# LEF abstracts for the cells placed in sample.gds
# fetched from google/skywater-pdk-libs-sky130_fd_sc_hd

VERSION 5.5 ;
BUSBITCHARS "[]" ;
DIVIDERCHAR "/" ;

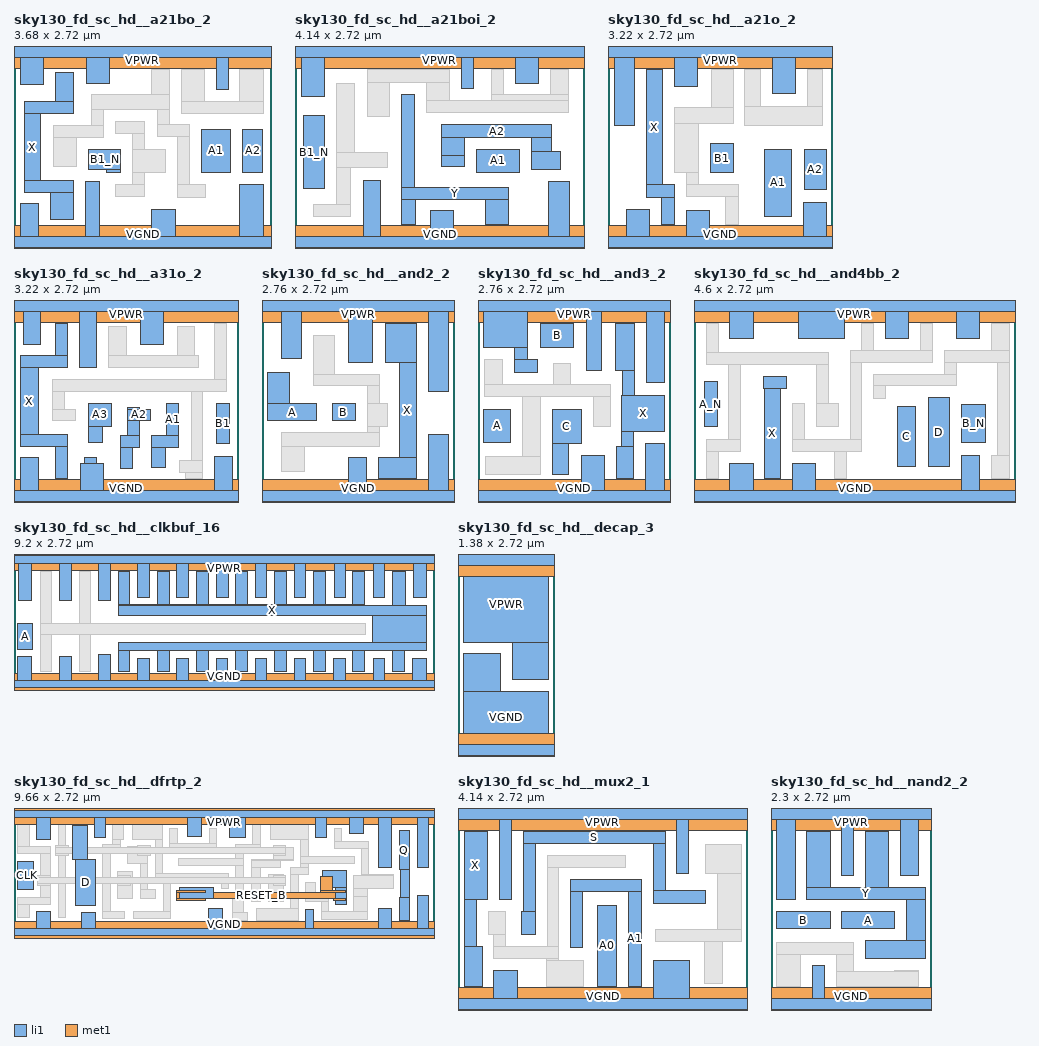
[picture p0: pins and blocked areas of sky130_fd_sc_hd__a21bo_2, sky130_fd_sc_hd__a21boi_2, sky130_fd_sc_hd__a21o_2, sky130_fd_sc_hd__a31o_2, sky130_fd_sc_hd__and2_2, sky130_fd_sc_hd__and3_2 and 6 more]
MACRO sky130_fd_sc_hd__a21bo_2
  CLASS CORE ;
  SOURCE USER ;
  ORIGIN  0.000000  0.000000 ;
  SIZE  3.680000 BY  2.720000 ;
  SYMMETRY X Y R90 ;
  SITE unithd ;
  PIN A1
    ANTENNAGATEAREA  0.247500 ;
    DIRECTION INPUT ;
    USE SIGNAL ;
    PORT
      LAYER li1 ;
        RECT 2.685000 0.995000 3.100000 1.615000 ;
    END
  END A1
  PIN A2
    ANTENNAGATEAREA  0.247500 ;
    DIRECTION INPUT ;
    USE SIGNAL ;
    PORT
      LAYER li1 ;
        RECT 3.270000 0.995000 3.560000 1.615000 ;
    END
  END A2
  PIN B1_N
    ANTENNAGATEAREA  0.126000 ;
    DIRECTION INPUT ;
    USE SIGNAL ;
    PORT
      LAYER li1 ;
        RECT 1.070000 1.035000 1.525000 1.325000 ;
        RECT 1.330000 0.995000 1.525000 1.035000 ;
    END
  END B1_N
  PIN X
    ANTENNADIFFAREA  0.462000 ;
    DIRECTION OUTPUT ;
    USE SIGNAL ;
    PORT
      LAYER li1 ;
        RECT 0.150000 0.715000 0.850000 0.885000 ;
        RECT 0.150000 0.885000 0.380000 1.835000 ;
        RECT 0.150000 1.835000 0.850000 2.005000 ;
        RECT 0.520000 0.315000 0.850000 0.715000 ;
        RECT 0.595000 2.005000 0.850000 2.425000 ;
    END
  END X
  PIN VGND
    DIRECTION INOUT ;
    SHAPE ABUTMENT ;
    USE GROUND ;
    PORT
      LAYER li1 ;
        RECT 0.000000 -0.085000 3.680000 0.085000 ;
        RECT 0.090000  0.085000 0.345000 0.545000 ;
        RECT 1.020000  0.085000 1.220000 0.865000 ;
        RECT 1.975000  0.085000 2.305000 0.465000 ;
        RECT 3.235000  0.085000 3.565000 0.825000 ;
    END
    PORT
      LAYER met1 ;
        RECT 0.000000 -0.240000 3.680000 0.240000 ;
    END
  END VGND
  PIN VPWR
    DIRECTION INOUT ;
    SHAPE ABUTMENT ;
    USE POWER ;
    PORT
      LAYER li1 ;
        RECT 0.000000 2.635000 3.680000 2.805000 ;
        RECT 0.090000 2.255000 0.425000 2.635000 ;
        RECT 1.040000 2.275000 1.370000 2.635000 ;
        RECT 2.895000 2.185000 3.065000 2.635000 ;
    END
    PORT
      LAYER met1 ;
        RECT 0.000000 2.480000 3.680000 2.960000 ;
    END
  END VPWR
  OBS
    LAYER li1 ;
      RECT 0.570000 1.075000 0.900000 1.495000 ;
      RECT 0.570000 1.495000 1.285000 1.665000 ;
      RECT 1.115000 1.665000 1.285000 1.895000 ;
      RECT 1.115000 1.895000 2.225000 2.105000 ;
      RECT 1.455000 0.655000 1.865000 0.825000 ;
      RECT 1.455000 1.555000 1.865000 1.725000 ;
      RECT 1.695000 0.825000 1.865000 0.995000 ;
      RECT 1.695000 0.995000 2.175000 1.325000 ;
      RECT 1.695000 1.325000 1.865000 1.555000 ;
      RECT 1.975000 2.105000 2.225000 2.465000 ;
      RECT 2.055000 1.505000 2.515000 1.675000 ;
      RECT 2.055000 1.675000 2.225000 1.895000 ;
      RECT 2.345000 0.635000 2.740000 0.825000 ;
      RECT 2.345000 0.825000 2.515000 1.505000 ;
      RECT 2.395000 1.845000 3.565000 2.015000 ;
      RECT 2.395000 2.015000 2.725000 2.465000 ;
      RECT 3.235000 2.015000 3.565000 2.465000 ;
  END
END sky130_fd_sc_hd__a21bo_2
MACRO sky130_fd_sc_hd__a21boi_2
  CLASS CORE ;
  SOURCE USER ;
  ORIGIN  0.000000  0.000000 ;
  SIZE  4.140000 BY  2.720000 ;
  SYMMETRY X Y R90 ;
  SITE unithd ;
  PIN A1
    ANTENNAGATEAREA  0.495000 ;
    DIRECTION INPUT ;
    USE SIGNAL ;
    PORT
      LAYER li1 ;
        RECT 2.605000 0.995000 3.215000 1.325000 ;
    END
  END A1
  PIN A2
    ANTENNAGATEAREA  0.495000 ;
    DIRECTION INPUT ;
    USE SIGNAL ;
    PORT
      LAYER li1 ;
        RECT 2.095000 1.075000 2.425000 1.245000 ;
        RECT 2.100000 1.245000 2.425000 1.495000 ;
        RECT 2.100000 1.495000 3.675000 1.675000 ;
        RECT 3.385000 1.035000 3.795000 1.295000 ;
        RECT 3.385000 1.295000 3.675000 1.495000 ;
    END
  END A2
  PIN B1_N
    ANTENNAGATEAREA  0.126000 ;
    DIRECTION INPUT ;
    USE SIGNAL ;
    PORT
      LAYER li1 ;
        RECT 0.120000 0.765000 0.425000 1.805000 ;
    END
  END B1_N
  PIN Y
    ANTENNADIFFAREA  0.627500 ;
    DIRECTION OUTPUT ;
    USE SIGNAL ;
    PORT
      LAYER li1 ;
        RECT 1.520000 0.255000 1.720000 0.615000 ;
        RECT 1.520000 0.615000 3.060000 0.785000 ;
        RECT 1.520000 0.785000 1.715000 2.115000 ;
        RECT 2.730000 0.255000 3.060000 0.615000 ;
    END
  END Y
  PIN VGND
    DIRECTION INOUT ;
    SHAPE ABUTMENT ;
    USE GROUND ;
    PORT
      LAYER li1 ;
        RECT 0.000000 -0.085000 4.140000 0.085000 ;
        RECT 0.985000  0.085000 1.225000 0.885000 ;
        RECT 1.940000  0.085000 2.270000 0.445000 ;
        RECT 3.635000  0.085000 3.930000 0.865000 ;
    END
    PORT
      LAYER met1 ;
        RECT 0.000000 -0.240000 4.140000 0.240000 ;
    END
  END VGND
  PIN VPWR
    DIRECTION INOUT ;
    SHAPE ABUTMENT ;
    USE POWER ;
    PORT
      LAYER li1 ;
        RECT 0.000000 2.635000 4.140000 2.805000 ;
        RECT 0.095000 2.080000 0.425000 2.635000 ;
        RECT 2.385000 2.195000 2.555000 2.635000 ;
        RECT 3.160000 2.275000 3.490000 2.635000 ;
    END
    PORT
      LAYER met1 ;
        RECT 0.000000 2.480000 4.140000 2.960000 ;
    END
  END VPWR
  OBS
    LAYER li1 ;
      RECT 0.265000 0.360000 0.795000 0.530000 ;
      RECT 0.595000 0.530000 0.795000 1.070000 ;
      RECT 0.595000 1.070000 1.325000 1.285000 ;
      RECT 0.595000 1.285000 0.855000 2.265000 ;
      RECT 1.045000 1.795000 1.350000 2.285000 ;
      RECT 1.045000 2.285000 2.215000 2.465000 ;
      RECT 1.885000 1.855000 3.920000 2.025000 ;
      RECT 1.885000 2.025000 2.215000 2.285000 ;
      RECT 2.810000 2.025000 3.920000 2.105000 ;
      RECT 2.810000 2.105000 2.980000 2.465000 ;
      RECT 3.660000 2.105000 3.920000 2.465000 ;
  END
END sky130_fd_sc_hd__a21boi_2
MACRO sky130_fd_sc_hd__a21o_2
  CLASS CORE ;
  SOURCE USER ;
  ORIGIN  0.000000  0.000000 ;
  SIZE  3.220000 BY  2.720000 ;
  SYMMETRY X Y R90 ;
  SITE unithd ;
  PIN A1
    ANTENNAGATEAREA  0.247500 ;
    DIRECTION INPUT ;
    USE SIGNAL ;
    PORT
      LAYER li1 ;
        RECT 2.240000 0.365000 2.620000 1.325000 ;
    END
  END A1
  PIN A2
    ANTENNAGATEAREA  0.247500 ;
    DIRECTION INPUT ;
    USE SIGNAL ;
    PORT
      LAYER li1 ;
        RECT 2.810000 0.750000 3.125000 1.325000 ;
    END
  END A2
  PIN B1
    ANTENNAGATEAREA  0.247500 ;
    DIRECTION INPUT ;
    USE SIGNAL ;
    PORT
      LAYER li1 ;
        RECT 1.465000 0.995000 1.790000 1.410000 ;
    END
  END B1
  PIN X
    ANTENNADIFFAREA  0.462000 ;
    DIRECTION OUTPUT ;
    USE SIGNAL ;
    PORT
      LAYER li1 ;
        RECT 0.555000 0.635000 0.955000 0.825000 ;
        RECT 0.555000 0.825000 0.785000 2.465000 ;
        RECT 0.765000 0.255000 0.955000 0.635000 ;
    END
  END X
  PIN VGND
    DIRECTION INOUT ;
    SHAPE ABUTMENT ;
    USE GROUND ;
    PORT
      LAYER li1 ;
        RECT 0.000000 -0.085000 3.220000 0.085000 ;
        RECT 0.265000  0.085000 0.595000 0.465000 ;
        RECT 1.125000  0.085000 1.455000 0.445000 ;
        RECT 2.805000  0.085000 3.135000 0.565000 ;
    END
    PORT
      LAYER met1 ;
        RECT 0.000000 -0.240000 3.220000 0.240000 ;
    END
  END VGND
  PIN VPWR
    DIRECTION INOUT ;
    SHAPE ABUTMENT ;
    USE POWER ;
    PORT
      LAYER li1 ;
        RECT 0.000000 2.635000 3.220000 2.805000 ;
        RECT 0.095000 1.665000 0.385000 2.635000 ;
        RECT 0.955000 2.220000 1.285000 2.635000 ;
        RECT 2.355000 2.125000 2.685000 2.635000 ;
    END
    PORT
      LAYER met1 ;
        RECT 0.000000 2.480000 3.220000 2.960000 ;
    END
  END VPWR
  OBS
    LAYER li1 ;
      RECT 0.955000 0.995000 1.295000 1.690000 ;
      RECT 0.955000 1.690000 1.790000 1.920000 ;
      RECT 1.125000 0.655000 1.865000 0.825000 ;
      RECT 1.125000 0.825000 1.295000 0.995000 ;
      RECT 1.475000 1.920000 1.790000 2.465000 ;
      RECT 1.675000 0.255000 1.865000 0.655000 ;
      RECT 1.960000 1.670000 3.075000 1.935000 ;
      RECT 1.960000 1.935000 2.185000 2.465000 ;
      RECT 2.855000 1.935000 3.075000 2.465000 ;
  END
END sky130_fd_sc_hd__a21o_2
MACRO sky130_fd_sc_hd__a31o_2
  CLASS CORE ;
  SOURCE USER ;
  ORIGIN  0.000000  0.000000 ;
  SIZE  3.220000 BY  2.720000 ;
  SYMMETRY X Y R90 ;
  SITE unithd ;
  PIN A1
    ANTENNAGATEAREA  0.247500 ;
    DIRECTION INPUT ;
    USE SIGNAL ;
    PORT
      LAYER li1 ;
        RECT 1.965000 0.415000 2.175000 0.700000 ;
        RECT 1.965000 0.700000 2.355000 0.870000 ;
        RECT 2.185000 0.870000 2.355000 1.325000 ;
    END
  END A1
  PIN A2
    ANTENNAGATEAREA  0.247500 ;
    DIRECTION INPUT ;
    USE SIGNAL ;
    PORT
      LAYER li1 ;
        RECT 1.530000 0.400000 1.700000 0.695000 ;
        RECT 1.530000 0.695000 1.795000 0.865000 ;
        RECT 1.625000 0.865000 1.795000 1.075000 ;
        RECT 1.625000 1.075000 1.955000 1.245000 ;
        RECT 1.625000 1.245000 1.795000 1.260000 ;
    END
  END A2
  PIN A3
    ANTENNAGATEAREA  0.247500 ;
    DIRECTION INPUT ;
    USE SIGNAL ;
    PORT
      LAYER li1 ;
        RECT 1.065000 0.760000 1.270000 0.995000 ;
        RECT 1.065000 0.995000 1.395000 1.325000 ;
    END
  END A3
  PIN B1
    ANTENNAGATEAREA  0.247500 ;
    DIRECTION INPUT ;
    USE SIGNAL ;
    PORT
      LAYER li1 ;
        RECT 2.895000 0.755000 3.090000 1.325000 ;
    END
  END B1
  PIN X
    ANTENNADIFFAREA  0.445500 ;
    DIRECTION OUTPUT ;
    USE SIGNAL ;
    PORT
      LAYER li1 ;
        RECT 0.090000 0.715000 0.765000 0.885000 ;
        RECT 0.090000 0.885000 0.345000 1.835000 ;
        RECT 0.090000 1.835000 0.765000 2.005000 ;
        RECT 0.595000 0.255000 0.765000 0.715000 ;
        RECT 0.595000 2.005000 0.765000 2.465000 ;
    END
  END X
  PIN VGND
    DIRECTION INOUT ;
    SHAPE ABUTMENT ;
    USE GROUND ;
    PORT
      LAYER li1 ;
        RECT 0.000000 -0.085000 3.220000 0.085000 ;
        RECT 0.090000  0.085000 0.345000 0.545000 ;
        RECT 0.955000  0.085000 1.285000 0.465000 ;
        RECT 1.015000  0.465000 1.185000 0.545000 ;
        RECT 2.875000  0.085000 3.135000 0.565000 ;
    END
    PORT
      LAYER met1 ;
        RECT 0.000000 -0.240000 3.220000 0.240000 ;
    END
  END VGND
  PIN VPWR
    DIRECTION INOUT ;
    SHAPE ABUTMENT ;
    USE POWER ;
    PORT
      LAYER li1 ;
        RECT 0.000000 2.635000 3.220000 2.805000 ;
        RECT 0.135000 2.175000 0.385000 2.635000 ;
        RECT 0.935000 1.835000 1.185000 2.635000 ;
        RECT 1.815000 2.175000 2.145000 2.635000 ;
    END
    PORT
      LAYER met1 ;
        RECT 0.000000 2.480000 3.220000 2.960000 ;
    END
  END VPWR
  OBS
    LAYER li1 ;
      RECT 0.555000 1.075000 0.885000 1.245000 ;
      RECT 0.555000 1.245000 0.725000 1.495000 ;
      RECT 0.555000 1.495000 3.045000 1.665000 ;
      RECT 1.355000 1.835000 2.645000 2.005000 ;
      RECT 1.355000 2.005000 1.605000 2.425000 ;
      RECT 2.335000 2.005000 2.585000 2.425000 ;
      RECT 2.375000 0.335000 2.705000 0.505000 ;
      RECT 2.460000 0.255000 2.705000 0.335000 ;
      RECT 2.535000 0.505000 2.705000 1.495000 ;
      RECT 2.875000 1.665000 3.045000 2.465000 ;
  END
END sky130_fd_sc_hd__a31o_2
MACRO sky130_fd_sc_hd__and2_2
  CLASS CORE ;
  SOURCE USER ;
  ORIGIN  0.000000  0.000000 ;
  SIZE  2.760000 BY  2.720000 ;
  SYMMETRY X Y R90 ;
  SITE unithd ;
  PIN A
    ANTENNAGATEAREA  0.126000 ;
    DIRECTION INPUT ;
    USE SIGNAL ;
    PORT
      LAYER li1 ;
        RECT 0.085000 1.075000 0.775000 1.325000 ;
        RECT 0.085000 1.325000 0.400000 1.765000 ;
    END
  END A
  PIN B
    ANTENNAGATEAREA  0.126000 ;
    DIRECTION INPUT ;
    USE SIGNAL ;
    PORT
      LAYER li1 ;
        RECT 1.005000 1.075000 1.335000 1.325000 ;
    END
  END B
  PIN X
    ANTENNADIFFAREA  0.643500 ;
    DIRECTION OUTPUT ;
    USE SIGNAL ;
    PORT
      LAYER li1 ;
        RECT 1.665000 0.255000 2.215000 0.545000 ;
        RECT 1.765000 1.915000 2.215000 2.465000 ;
        RECT 1.965000 0.545000 2.215000 1.915000 ;
    END
  END X
  PIN VGND
    DIRECTION INOUT ;
    SHAPE ABUTMENT ;
    USE GROUND ;
    PORT
      LAYER li1 ;
        RECT 0.000000 -0.085000 2.760000 0.085000 ;
        RECT 1.245000  0.085000 1.495000 0.545000 ;
        RECT 2.385000  0.085000 2.675000 0.885000 ;
    END
    PORT
      LAYER met1 ;
        RECT 0.000000 -0.240000 2.760000 0.240000 ;
    END
  END VGND
  PIN VPWR
    DIRECTION INOUT ;
    SHAPE ABUTMENT ;
    USE POWER ;
    PORT
      LAYER li1 ;
        RECT 0.000000 2.635000 2.760000 2.805000 ;
        RECT 0.285000 1.965000 0.565000 2.635000 ;
        RECT 1.245000 1.915000 1.575000 2.635000 ;
        RECT 2.385000 1.495000 2.675000 2.635000 ;
    END
    PORT
      LAYER met1 ;
        RECT 0.000000 2.480000 2.760000 2.960000 ;
    END
  END VPWR
  OBS
    LAYER li1 ;
      RECT 0.285000 0.355000 0.615000 0.715000 ;
      RECT 0.285000 0.715000 1.675000 0.905000 ;
      RECT 0.735000 1.575000 1.675000 1.745000 ;
      RECT 0.735000 1.745000 1.035000 2.295000 ;
      RECT 1.505000 0.905000 1.675000 0.995000 ;
      RECT 1.505000 0.995000 1.795000 1.325000 ;
      RECT 1.505000 1.325000 1.675000 1.575000 ;
  END
END sky130_fd_sc_hd__and2_2
MACRO sky130_fd_sc_hd__and3_2
  CLASS CORE ;
  SOURCE USER ;
  ORIGIN  0.000000  0.000000 ;
  SIZE  2.760000 BY  2.720000 ;
  SYMMETRY X Y R90 ;
  SITE unithd ;
  PIN A
    ANTENNAGATEAREA  0.126000 ;
    DIRECTION INPUT ;
    USE SIGNAL ;
    PORT
      LAYER li1 ;
        RECT 0.085000 0.765000 0.470000 1.245000 ;
    END
  END A
  PIN B
    ANTENNAGATEAREA  0.126000 ;
    DIRECTION INPUT ;
    USE SIGNAL ;
    PORT
      LAYER li1 ;
        RECT 0.895000 2.125000 1.370000 2.465000 ;
    END
  END B
  PIN C
    ANTENNAGATEAREA  0.126000 ;
    DIRECTION INPUT ;
    USE SIGNAL ;
    PORT
      LAYER li1 ;
        RECT 1.065000 0.305000 1.295000 0.750000 ;
        RECT 1.065000 0.750000 1.475000 1.245000 ;
    END
  END C
  PIN X
    ANTENNADIFFAREA  0.445500 ;
    DIRECTION OUTPUT ;
    USE SIGNAL ;
    PORT
      LAYER li1 ;
        RECT 1.970000 1.795000 2.245000 2.465000 ;
        RECT 1.980000 0.255000 2.230000 0.715000 ;
        RECT 2.060000 0.715000 2.230000 0.925000 ;
        RECT 2.060000 0.925000 2.675000 1.445000 ;
        RECT 2.075000 1.445000 2.245000 1.795000 ;
    END
  END X
  PIN VGND
    DIRECTION INOUT ;
    SHAPE ABUTMENT ;
    USE GROUND ;
    PORT
      LAYER li1 ;
        RECT 0.000000 -0.085000 2.760000 0.085000 ;
        RECT 1.475000  0.085000 1.805000 0.580000 ;
        RECT 2.400000  0.085000 2.675000 0.745000 ;
    END
    PORT
      LAYER met1 ;
        RECT 0.000000 -0.240000 2.760000 0.240000 ;
    END
  END VGND
  PIN VPWR
    DIRECTION INOUT ;
    SHAPE ABUTMENT ;
    USE POWER ;
    PORT
      LAYER li1 ;
        RECT 0.000000 2.635000 2.760000 2.805000 ;
        RECT 0.085000 2.130000 0.715000 2.635000 ;
        RECT 0.525000 1.765000 0.855000 1.955000 ;
        RECT 0.525000 1.955000 0.715000 2.130000 ;
        RECT 1.555000 1.790000 1.770000 2.635000 ;
        RECT 2.415000 1.625000 2.675000 2.635000 ;
    END
    PORT
      LAYER met1 ;
        RECT 0.000000 2.480000 2.760000 2.960000 ;
    END
  END VPWR
  OBS
    LAYER li1 ;
      RECT 0.100000 1.425000 1.890000 1.595000 ;
      RECT 0.100000 1.595000 0.355000 1.960000 ;
      RECT 0.105000 0.305000 0.895000 0.570000 ;
      RECT 0.640000 0.570000 0.895000 1.425000 ;
      RECT 1.080000 1.595000 1.330000 1.890000 ;
      RECT 1.660000 0.995000 1.890000 1.425000 ;
  END
END sky130_fd_sc_hd__and3_2
MACRO sky130_fd_sc_hd__and4bb_2
  CLASS CORE ;
  SOURCE USER ;
  ORIGIN  0.000000  0.000000 ;
  SIZE  4.600000 BY  2.720000 ;
  SYMMETRY X Y R90 ;
  SITE unithd ;
  PIN A_N
    ANTENNAGATEAREA  0.126000 ;
    DIRECTION INPUT ;
    USE SIGNAL ;
    PORT
      LAYER li1 ;
        RECT 0.150000 0.995000 0.330000 1.635000 ;
    END
  END A_N
  PIN B_N
    ANTENNAGATEAREA  0.126000 ;
    DIRECTION INPUT ;
    USE SIGNAL ;
    PORT
      LAYER li1 ;
        RECT 3.825000 0.765000 4.175000 1.305000 ;
    END
  END B_N
  PIN C
    ANTENNAGATEAREA  0.126000 ;
    DIRECTION INPUT ;
    USE SIGNAL ;
    PORT
      LAYER li1 ;
        RECT 2.910000 0.420000 3.175000 1.275000 ;
    END
  END C
  PIN D
    ANTENNAGATEAREA  0.126000 ;
    DIRECTION INPUT ;
    USE SIGNAL ;
    PORT
      LAYER li1 ;
        RECT 3.350000 0.425000 3.655000 1.405000 ;
    END
  END D
  PIN X
    ANTENNADIFFAREA  0.445500 ;
    DIRECTION OUTPUT ;
    USE SIGNAL ;
    PORT
      LAYER li1 ;
        RECT 0.990000 1.545000 1.320000 1.715000 ;
        RECT 1.015000 0.255000 1.240000 1.545000 ;
    END
  END X
  PIN VGND
    DIRECTION INOUT ;
    SHAPE ABUTMENT ;
    USE GROUND ;
    PORT
      LAYER li1 ;
        RECT 0.000000 -0.085000 4.600000 0.085000 ;
        RECT 0.515000  0.085000 0.845000 0.465000 ;
        RECT 1.410000  0.085000 1.740000 0.465000 ;
        RECT 3.835000  0.085000 4.085000 0.585000 ;
    END
    PORT
      LAYER met1 ;
        RECT 0.000000 -0.240000 4.600000 0.240000 ;
    END
  END VGND
  PIN VPWR
    DIRECTION INOUT ;
    SHAPE ABUTMENT ;
    USE POWER ;
    PORT
      LAYER li1 ;
        RECT 0.000000 2.635000 4.600000 2.805000 ;
        RECT 0.515000 2.255000 0.845000 2.635000 ;
        RECT 1.490000 2.255000 2.160000 2.635000 ;
        RECT 2.735000 2.255000 3.075000 2.635000 ;
        RECT 3.755000 2.255000 4.085000 2.635000 ;
    END
    PORT
      LAYER met1 ;
        RECT 0.000000 2.480000 4.600000 2.960000 ;
    END
  END VPWR
  OBS
    LAYER li1 ;
      RECT 0.175000 0.255000 0.345000 0.635000 ;
      RECT 0.175000 0.635000 0.670000 0.805000 ;
      RECT 0.175000 1.885000 1.925000 2.055000 ;
      RECT 0.175000 2.055000 0.345000 2.465000 ;
      RECT 0.500000 0.805000 0.670000 1.885000 ;
      RECT 1.415000 0.635000 2.405000 0.805000 ;
      RECT 1.415000 0.805000 1.585000 1.325000 ;
      RECT 1.755000 0.995000 2.065000 1.325000 ;
      RECT 1.755000 1.325000 1.925000 1.885000 ;
      RECT 2.010000 0.255000 2.180000 0.635000 ;
      RECT 2.235000 0.805000 2.405000 1.915000 ;
      RECT 2.235000 1.915000 3.415000 2.085000 ;
      RECT 2.395000 2.085000 2.565000 2.465000 ;
      RECT 2.575000 1.400000 2.745000 1.575000 ;
      RECT 2.575000 1.575000 3.755000 1.745000 ;
      RECT 3.245000 2.085000 3.415000 2.465000 ;
      RECT 3.585000 1.745000 3.755000 1.915000 ;
      RECT 3.585000 1.915000 4.515000 2.085000 ;
      RECT 4.255000 0.255000 4.515000 0.585000 ;
      RECT 4.255000 2.085000 4.515000 2.465000 ;
      RECT 4.345000 0.585000 4.515000 1.915000 ;
  END
END sky130_fd_sc_hd__and4bb_2
MACRO sky130_fd_sc_hd__clkbuf_16
  CLASS CORE ;
  SOURCE USER ;
  ORIGIN  0.000000  0.000000 ;
  SIZE  9.200000 BY  2.720000 ;
  SYMMETRY X Y R90 ;
  SITE unithd ;
  PIN A
    ANTENNAGATEAREA  0.852000 ;
    DIRECTION INPUT ;
    USE SIGNAL ;
    PORT
      LAYER li1 ;
        RECT 0.085000 0.765000 0.400000 1.325000 ;
    END
  END A
  PIN X
    ANTENNADIFFAREA  3.180800 ;
    DIRECTION OUTPUT ;
    USE SIGNAL ;
    PORT
      LAYER li1 ;
        RECT 2.280000 0.280000 2.540000 0.735000 ;
        RECT 2.280000 0.735000 9.025000 0.905000 ;
        RECT 2.280000 1.495000 9.025000 1.720000 ;
        RECT 2.280000 1.720000 7.685000 1.735000 ;
        RECT 2.280000 1.735000 2.540000 2.460000 ;
        RECT 3.140000 0.280000 3.400000 0.735000 ;
        RECT 3.140000 1.735000 3.400000 2.460000 ;
        RECT 4.000000 0.280000 4.260000 0.735000 ;
        RECT 4.000000 1.735000 4.260000 2.460000 ;
        RECT 4.845000 0.280000 5.120000 0.735000 ;
        RECT 4.860000 1.735000 5.120000 2.460000 ;
        RECT 5.705000 0.280000 5.965000 0.735000 ;
        RECT 5.705000 1.735000 5.965000 2.460000 ;
        RECT 6.565000 0.280000 6.825000 0.735000 ;
        RECT 6.565000 1.735000 6.825000 2.460000 ;
        RECT 7.425000 0.280000 7.685000 0.735000 ;
        RECT 7.425000 1.735000 7.685000 2.460000 ;
        RECT 7.860000 0.905000 9.025000 1.495000 ;
        RECT 8.295000 0.280000 8.555000 0.735000 ;
        RECT 8.295000 1.720000 8.585000 2.460000 ;
    END
  END X
  PIN VGND
    DIRECTION INOUT ;
    SHAPE ABUTMENT ;
    USE GROUND ;
    PORT
      LAYER li1 ;
        RECT 0.000000 -0.085000 9.200000 0.085000 ;
        RECT 0.085000  0.085000 0.390000 0.595000 ;
        RECT 0.990000  0.085000 1.250000 0.610000 ;
        RECT 1.850000  0.085000 2.110000 0.645000 ;
        RECT 2.710000  0.085000 2.970000 0.565000 ;
        RECT 3.570000  0.085000 3.830000 0.565000 ;
        RECT 4.430000  0.085000 4.675000 0.565000 ;
        RECT 5.290000  0.085000 5.535000 0.565000 ;
        RECT 6.145000  0.085000 6.395000 0.565000 ;
        RECT 7.005000  0.085000 7.255000 0.565000 ;
        RECT 7.865000  0.085000 8.125000 0.565000 ;
        RECT 8.725000  0.085000 9.025000 0.565000 ;
    END
    PORT
      LAYER met1 ;
        RECT 0.000000 -0.240000 9.200000 0.240000 ;
    END
  END VGND
  PIN VPWR
    DIRECTION INOUT ;
    SHAPE ABUTMENT ;
    USE POWER ;
    PORT
      LAYER li1 ;
        RECT 0.000000 2.635000 9.200000 2.805000 ;
        RECT 0.095000 1.825000 0.390000 2.635000 ;
        RECT 0.990000 1.825000 1.250000 2.635000 ;
        RECT 1.850000 1.835000 2.110000 2.630000 ;
        RECT 1.850000 2.630000 8.125000 2.635000 ;
        RECT 2.710000 1.905000 2.970000 2.630000 ;
        RECT 3.570000 1.905000 3.830000 2.630000 ;
        RECT 4.430000 1.905000 4.690000 2.630000 ;
        RECT 5.290000 1.905000 5.535000 2.630000 ;
        RECT 6.150000 1.905000 6.395000 2.630000 ;
        RECT 7.010000 1.905000 7.255000 2.630000 ;
        RECT 7.870000 1.905000 8.125000 2.630000 ;
        RECT 8.755000 1.890000 9.025000 2.635000 ;
    END
    PORT
      LAYER met1 ;
        RECT 0.000000 2.480000 9.200000 2.960000 ;
    END
  END VPWR
  OBS
    LAYER li1 ;
      RECT 0.570000 0.265000 0.820000 1.075000 ;
      RECT 0.570000 1.075000 7.690000 1.325000 ;
      RECT 0.570000 1.325000 0.815000 2.465000 ;
      RECT 1.430000 0.265000 1.680000 1.075000 ;
      RECT 1.430000 1.325000 1.680000 2.460000 ;
  END
END sky130_fd_sc_hd__clkbuf_16
MACRO sky130_fd_sc_hd__decap_3
  CLASS CORE ;
  SOURCE USER ;
  ORIGIN  0.000000  0.000000 ;
  SIZE  1.380000 BY  2.720000 ;
  SYMMETRY X Y R90 ;
  SITE unithd ;
  PIN VGND
    DIRECTION INOUT ;
    SHAPE ABUTMENT ;
    USE GROUND ;
    PORT
      LAYER li1 ;
        RECT 0.000000 -0.085000 1.380000 0.085000 ;
        RECT 0.085000  0.085000 1.295000 0.835000 ;
        RECT 0.085000  0.835000 0.605000 1.375000 ;
    END
    PORT
      LAYER met1 ;
        RECT 0.000000 -0.240000 1.380000 0.240000 ;
    END
  END VGND
  PIN VPWR
    DIRECTION INOUT ;
    SHAPE ABUTMENT ;
    USE POWER ;
    PORT
      LAYER li1 ;
        RECT 0.000000 2.635000 1.380000 2.805000 ;
        RECT 0.085000 1.545000 1.295000 2.635000 ;
        RECT 0.775000 1.005000 1.295000 1.545000 ;
    END
    PORT
      LAYER met1 ;
        RECT 0.000000 2.480000 1.380000 2.960000 ;
    END
  END VPWR
  OBS
  END
END sky130_fd_sc_hd__decap_3
MACRO sky130_fd_sc_hd__dfrtp_2
  CLASS CORE ;
  SOURCE USER ;
  ORIGIN  0.000000  0.000000 ;
  SIZE  9.660000 BY  2.720000 ;
  SYMMETRY X Y R90 ;
  SITE unithd ;
  PIN D
    ANTENNAGATEAREA  0.126000 ;
    DIRECTION INPUT ;
    USE SIGNAL ;
    PORT
      LAYER li1 ;
        RECT 1.355000 1.665000 1.680000 2.450000 ;
        RECT 1.415000 0.615000 1.875000 1.665000 ;
    END
  END D
  PIN Q
    ANTENNADIFFAREA  0.445500 ;
    DIRECTION OUTPUT ;
    USE SIGNAL ;
    PORT
      LAYER li1 ;
        RECT 8.855000 0.265000 9.105000 0.795000 ;
        RECT 8.855000 1.445000 9.105000 2.325000 ;
        RECT 8.900000 0.795000 9.105000 1.445000 ;
    END
  END Q
  PIN RESET_B
    ANTENNAGATEAREA  0.252000 ;
    DIRECTION INPUT ;
    USE SIGNAL ;
    PORT
      LAYER li1 ;
        RECT 3.805000 0.765000 4.595000 1.015000 ;
    END
    PORT
      LAYER li1 ;
        RECT 7.105000 1.035000 7.645000 1.405000 ;
        RECT 7.405000 0.635000 7.645000 1.035000 ;
    END
    PORT
      LAYER met1 ;
        RECT 3.745000 0.735000 4.395000 0.780000 ;
        RECT 3.745000 0.780000 7.635000 0.920000 ;
        RECT 3.745000 0.920000 4.395000 0.965000 ;
        RECT 7.045000 0.920000 7.635000 0.965000 ;
        RECT 7.045000 0.965000 7.335000 1.280000 ;
        RECT 7.345000 0.735000 7.635000 0.780000 ;
    END
  END RESET_B
  PIN CLK
    ANTENNAGATEAREA  0.159000 ;
    DIRECTION INPUT ;
    USE CLOCK ;
    PORT
      LAYER li1 ;
        RECT 0.090000 0.975000 0.440000 1.625000 ;
    END
  END CLK
  PIN VGND
    DIRECTION INOUT ;
    SHAPE ABUTMENT ;
    USE GROUND ;
    PORT
      LAYER li1 ;
        RECT 0.000000 -0.085000 9.660000 0.085000 ;
        RECT 0.515000  0.085000 0.845000 0.465000 ;
        RECT 1.545000  0.085000 1.875000 0.445000 ;
        RECT 4.475000  0.085000 4.805000 0.545000 ;
        RECT 6.705000  0.085000 6.895000 0.525000 ;
        RECT 8.380000  0.085000 8.685000 0.545000 ;
        RECT 9.275000  0.085000 9.525000 0.840000 ;
    END
    PORT
      LAYER met1 ;
        RECT 0.000000 -0.240000 9.660000 0.240000 ;
    END
  END VGND
  PIN VPWR
    DIRECTION INOUT ;
    SHAPE ABUTMENT ;
    USE POWER ;
    PORT
      LAYER li1 ;
        RECT 0.000000 2.635000 9.660000 2.805000 ;
        RECT 0.515000 2.135000 0.845000 2.635000 ;
        RECT 1.850000 2.175000 2.100000 2.635000 ;
        RECT 3.990000 2.205000 4.320000 2.635000 ;
        RECT 4.955000 2.175000 5.325000 2.635000 ;
        RECT 6.940000 2.175000 7.190000 2.635000 ;
        RECT 7.710000 2.255000 8.040000 2.635000 ;
        RECT 8.380000 1.495000 8.685000 2.635000 ;
        RECT 9.275000 1.495000 9.525000 2.635000 ;
    END
    PORT
      LAYER met1 ;
        RECT 0.000000 2.480000 9.660000 2.960000 ;
    END
  END VPWR
  OBS
    LAYER li1 ;
      RECT 0.090000 0.345000 0.345000 0.635000 ;
      RECT 0.090000 0.635000 0.840000 0.805000 ;
      RECT 0.090000 1.795000 0.840000 1.965000 ;
      RECT 0.090000 1.965000 0.345000 2.465000 ;
      RECT 0.610000 0.805000 0.840000 1.795000 ;
      RECT 1.015000 0.345000 1.185000 2.465000 ;
      RECT 2.045000 0.305000 2.540000 0.475000 ;
      RECT 2.045000 0.475000 2.215000 1.835000 ;
      RECT 2.045000 1.835000 2.440000 2.005000 ;
      RECT 2.270000 2.005000 2.440000 2.135000 ;
      RECT 2.270000 2.135000 2.520000 2.465000 ;
      RECT 2.385000 0.765000 2.735000 1.385000 ;
      RECT 2.610000 1.575000 3.075000 1.965000 ;
      RECT 2.735000 2.135000 3.415000 2.465000 ;
      RECT 2.745000 0.305000 3.600000 0.475000 ;
      RECT 2.905000 0.765000 3.260000 0.985000 ;
      RECT 2.905000 0.985000 3.075000 1.575000 ;
      RECT 3.245000 1.185000 4.935000 1.355000 ;
      RECT 3.245000 1.355000 3.415000 2.135000 ;
      RECT 3.430000 0.475000 3.600000 1.185000 ;
      RECT 3.585000 1.865000 4.660000 2.035000 ;
      RECT 3.585000 2.035000 3.755000 2.375000 ;
      RECT 3.775000 1.525000 5.275000 1.695000 ;
      RECT 4.490000 2.035000 4.660000 2.375000 ;
      RECT 4.765000 1.005000 4.935000 1.185000 ;
      RECT 5.015000 0.275000 5.365000 0.445000 ;
      RECT 5.015000 0.445000 5.275000 0.835000 ;
      RECT 5.105000 0.835000 5.275000 1.525000 ;
      RECT 5.105000 1.695000 5.275000 1.835000 ;
      RECT 5.105000 1.835000 5.665000 2.005000 ;
      RECT 5.465000 0.705000 5.675000 1.495000 ;
      RECT 5.465000 1.495000 6.140000 1.655000 ;
      RECT 5.465000 1.655000 6.430000 1.665000 ;
      RECT 5.495000 2.005000 5.665000 2.465000 ;
      RECT 5.585000 0.255000 6.535000 0.535000 ;
      RECT 5.845000 0.705000 6.195000 1.325000 ;
      RECT 5.900000 2.125000 6.770000 2.465000 ;
      RECT 5.970000 1.665000 6.430000 1.955000 ;
      RECT 6.365000 0.535000 6.535000 1.315000 ;
      RECT 6.365000 1.315000 6.770000 1.485000 ;
      RECT 6.600000 1.485000 6.770000 1.575000 ;
      RECT 6.600000 1.575000 7.820000 1.745000 ;
      RECT 6.600000 1.745000 6.770000 2.125000 ;
      RECT 6.705000 0.695000 7.235000 0.865000 ;
      RECT 6.705000 0.865000 6.925000 1.145000 ;
      RECT 7.065000 0.295000 8.135000 0.465000 ;
      RECT 7.065000 0.465000 7.235000 0.695000 ;
      RECT 7.360000 1.915000 8.160000 2.085000 ;
      RECT 7.360000 2.085000 7.530000 2.375000 ;
      RECT 7.815000 0.465000 8.135000 0.820000 ;
      RECT 7.815000 0.820000 8.140000 0.995000 ;
      RECT 7.815000 0.995000 8.730000 1.295000 ;
      RECT 7.990000 1.295000 8.730000 1.325000 ;
      RECT 7.990000 1.325000 8.160000 1.915000 ;
    LAYER mcon ;
      RECT 0.610000 1.105000 0.780000 1.275000 ;
      RECT 1.015000 1.785000 1.185000 1.955000 ;
      RECT 2.445000 1.105000 2.615000 1.275000 ;
      RECT 2.905000 1.785000 3.075000 1.955000 ;
      RECT 6.025000 1.105000 6.195000 1.275000 ;
      RECT 6.025000 1.785000 6.195000 1.955000 ;
    LAYER met1 ;
      RECT 0.550000 1.075000 0.840000 1.120000 ;
      RECT 0.550000 1.120000 6.255000 1.260000 ;
      RECT 0.550000 1.260000 0.840000 1.305000 ;
      RECT 0.955000 1.755000 1.245000 1.800000 ;
      RECT 0.955000 1.800000 6.255000 1.940000 ;
      RECT 0.955000 1.940000 1.245000 1.985000 ;
      RECT 2.385000 1.075000 2.675000 1.120000 ;
      RECT 2.385000 1.260000 2.675000 1.305000 ;
      RECT 2.845000 1.755000 3.135000 1.800000 ;
      RECT 2.845000 1.940000 3.135000 1.985000 ;
      RECT 5.965000 1.075000 6.255000 1.120000 ;
      RECT 5.965000 1.260000 6.255000 1.305000 ;
      RECT 5.965000 1.755000 6.255000 1.800000 ;
      RECT 5.965000 1.940000 6.255000 1.985000 ;
  END
END sky130_fd_sc_hd__dfrtp_2
MACRO sky130_fd_sc_hd__mux2_1
  CLASS CORE ;
  SOURCE USER ;
  ORIGIN  0.000000  0.000000 ;
  SIZE  4.140000 BY  2.720000 ;
  SYMMETRY X Y R90 ;
  SITE unithd ;
  PIN A0
    ANTENNAGATEAREA  0.126000 ;
    DIRECTION INPUT ;
    USE SIGNAL ;
    PORT
      LAYER li1 ;
        RECT 1.990000 0.255000 2.265000 1.415000 ;
    END
  END A0
  PIN A1
    ANTENNAGATEAREA  0.126000 ;
    DIRECTION INPUT ;
    USE SIGNAL ;
    PORT
      LAYER li1 ;
        RECT 1.615000 0.815000 1.785000 1.615000 ;
        RECT 1.615000 1.615000 2.625000 1.785000 ;
        RECT 2.435000 0.255000 2.625000 1.615000 ;
    END
  END A1
  PIN S
    ANTENNAGATEAREA  0.252000 ;
    DIRECTION INPUT ;
    USE SIGNAL ;
    PORT
      LAYER li1 ;
        RECT 0.910000 0.995000 1.105000 1.325000 ;
        RECT 0.935000 1.325000 1.105000 2.295000 ;
        RECT 0.935000 2.295000 2.965000 2.465000 ;
        RECT 2.795000 1.440000 3.545000 1.630000 ;
        RECT 2.795000 1.630000 2.965000 2.295000 ;
    END
  END S
  PIN X
    ANTENNADIFFAREA  0.429000 ;
    DIRECTION OUTPUT ;
    USE SIGNAL ;
    PORT
      LAYER li1 ;
        RECT 0.090000 0.255000 0.345000 0.825000 ;
        RECT 0.090000 0.825000 0.260000 1.495000 ;
        RECT 0.090000 1.495000 0.425000 2.465000 ;
    END
  END X
  PIN VGND
    DIRECTION INOUT ;
    SHAPE ABUTMENT ;
    USE GROUND ;
    PORT
      LAYER li1 ;
        RECT 0.000000 -0.085000 4.140000 0.085000 ;
        RECT 0.515000  0.085000 0.845000 0.485000 ;
        RECT 2.805000  0.085000 3.315000 0.620000 ;
    END
    PORT
      LAYER met1 ;
        RECT 0.000000 -0.240000 4.140000 0.240000 ;
    END
  END VGND
  PIN VPWR
    DIRECTION INOUT ;
    SHAPE ABUTMENT ;
    USE POWER ;
    PORT
      LAYER li1 ;
        RECT 0.000000 2.635000 4.140000 2.805000 ;
        RECT 0.595000 1.495000 0.765000 2.635000 ;
        RECT 3.135000 1.875000 3.305000 2.635000 ;
    END
    PORT
      LAYER met1 ;
        RECT 0.000000 2.480000 4.140000 2.960000 ;
    END
  END VPWR
  OBS
    LAYER li1 ;
      RECT 0.430000 0.995000 0.685000 1.325000 ;
      RECT 0.515000 0.655000 1.445000 0.825000 ;
      RECT 0.515000 0.825000 0.685000 0.995000 ;
      RECT 1.270000 0.255000 1.800000 0.620000 ;
      RECT 1.270000 0.620000 1.445000 0.655000 ;
      RECT 1.275000 0.825000 1.445000 1.955000 ;
      RECT 1.275000 1.955000 2.400000 2.125000 ;
      RECT 2.825000 0.895000 4.055000 1.065000 ;
      RECT 3.535000 0.290000 3.780000 0.895000 ;
      RECT 3.540000 1.875000 4.055000 2.285000 ;
      RECT 3.715000 1.065000 4.055000 1.875000 ;
  END
END sky130_fd_sc_hd__mux2_1
MACRO sky130_fd_sc_hd__nand2_2
  CLASS CORE ;
  SOURCE USER ;
  ORIGIN  0.000000  0.000000 ;
  SIZE  2.300000 BY  2.720000 ;
  SYMMETRY X Y R90 ;
  SITE unithd ;
  PIN A
    ANTENNAGATEAREA  0.495000 ;
    DIRECTION INPUT ;
    USE SIGNAL ;
    PORT
      LAYER li1 ;
        RECT 1.015000 1.075000 1.765000 1.325000 ;
    END
  END A
  PIN B
    ANTENNAGATEAREA  0.495000 ;
    DIRECTION INPUT ;
    USE SIGNAL ;
    PORT
      LAYER li1 ;
        RECT 0.085000 1.075000 0.845000 1.325000 ;
    END
  END B
  PIN Y
    ANTENNADIFFAREA  0.715500 ;
    DIRECTION OUTPUT ;
    USE SIGNAL ;
    PORT
      LAYER li1 ;
        RECT 0.515000 1.495000 2.215000 1.665000 ;
        RECT 0.515000 1.665000 0.845000 2.465000 ;
        RECT 1.355000 0.655000 2.215000 0.905000 ;
        RECT 1.355000 1.665000 1.685000 2.465000 ;
        RECT 1.935000 0.905000 2.215000 1.495000 ;
    END
  END Y
  PIN VGND
    DIRECTION INOUT ;
    SHAPE ABUTMENT ;
    USE GROUND ;
    PORT
      LAYER li1 ;
        RECT 0.000000 -0.085000 2.300000 0.085000 ;
        RECT 0.595000  0.085000 0.765000 0.545000 ;
    END
    PORT
      LAYER met1 ;
        RECT 0.000000 -0.240000 2.300000 0.240000 ;
    END
  END VGND
  PIN VPWR
    DIRECTION INOUT ;
    SHAPE ABUTMENT ;
    USE POWER ;
    PORT
      LAYER li1 ;
        RECT 0.000000 2.635000 2.300000 2.805000 ;
        RECT 0.085000 1.495000 0.345000 2.635000 ;
        RECT 1.015000 1.835000 1.185000 2.635000 ;
        RECT 1.855000 1.835000 2.110000 2.635000 ;
    END
    PORT
      LAYER met1 ;
        RECT 0.000000 2.480000 2.300000 2.960000 ;
    END
  END VPWR
  OBS
    LAYER li1 ;
      RECT 0.085000 0.255000 0.425000 0.715000 ;
      RECT 0.085000 0.715000 1.185000 0.885000 ;
      RECT 0.935000 0.255000 2.105000 0.465000 ;
      RECT 0.935000 0.465000 1.185000 0.715000 ;
      RECT 1.775000 0.465000 2.105000 0.485000 ;
  END
END sky130_fd_sc_hd__nand2_2
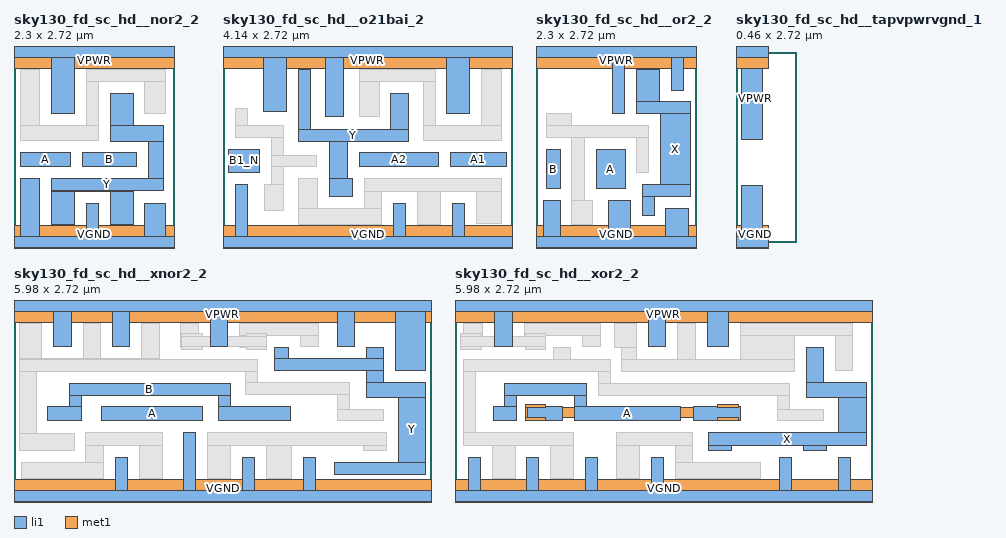
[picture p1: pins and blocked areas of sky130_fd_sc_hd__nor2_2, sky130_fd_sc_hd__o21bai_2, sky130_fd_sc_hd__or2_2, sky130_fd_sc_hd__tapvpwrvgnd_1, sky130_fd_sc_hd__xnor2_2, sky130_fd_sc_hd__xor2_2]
MACRO sky130_fd_sc_hd__nor2_2
  CLASS CORE ;
  SOURCE USER ;
  ORIGIN  0.000000  0.000000 ;
  SIZE  2.300000 BY  2.720000 ;
  SYMMETRY X Y R90 ;
  SITE unithd ;
  PIN A
    ANTENNAGATEAREA  0.495000 ;
    DIRECTION INPUT ;
    USE SIGNAL ;
    PORT
      LAYER li1 ;
        RECT 0.090000 1.075000 0.810000 1.275000 ;
    END
  END A
  PIN B
    ANTENNAGATEAREA  0.495000 ;
    DIRECTION INPUT ;
    USE SIGNAL ;
    PORT
      LAYER li1 ;
        RECT 0.980000 1.075000 1.750000 1.275000 ;
    END
  END B
  PIN Y
    ANTENNADIFFAREA  0.621000 ;
    DIRECTION OUTPUT ;
    USE SIGNAL ;
    PORT
      LAYER li1 ;
        RECT 0.535000 0.255000 0.865000 0.725000 ;
        RECT 0.535000 0.725000 1.705000 0.735000 ;
        RECT 0.535000 0.735000 2.135000 0.905000 ;
        RECT 1.375000 0.255000 1.705000 0.725000 ;
        RECT 1.375000 1.445000 2.135000 1.665000 ;
        RECT 1.375000 1.665000 1.705000 2.125000 ;
        RECT 1.920000 0.905000 2.135000 1.445000 ;
    END
  END Y
  PIN VGND
    DIRECTION INOUT ;
    SHAPE ABUTMENT ;
    USE GROUND ;
    PORT
      LAYER li1 ;
        RECT 0.000000 -0.085000 2.300000 0.085000 ;
        RECT 0.090000  0.085000 0.365000 0.905000 ;
        RECT 1.035000  0.085000 1.205000 0.555000 ;
        RECT 1.875000  0.085000 2.165000 0.555000 ;
    END
    PORT
      LAYER met1 ;
        RECT 0.000000 -0.240000 2.300000 0.240000 ;
    END
  END VGND
  PIN VPWR
    DIRECTION INOUT ;
    SHAPE ABUTMENT ;
    USE POWER ;
    PORT
      LAYER li1 ;
        RECT 0.000000 2.635000 2.300000 2.805000 ;
        RECT 0.535000 1.835000 0.865000 2.635000 ;
    END
    PORT
      LAYER met1 ;
        RECT 0.000000 2.480000 2.300000 2.960000 ;
    END
  END VPWR
  OBS
    LAYER li1 ;
      RECT 0.090000 1.455000 1.205000 1.665000 ;
      RECT 0.090000 1.665000 0.365000 2.465000 ;
      RECT 1.035000 1.665000 1.205000 2.295000 ;
      RECT 1.035000 2.295000 2.175000 2.465000 ;
      RECT 1.875000 1.835000 2.175000 2.295000 ;
  END
END sky130_fd_sc_hd__nor2_2
MACRO sky130_fd_sc_hd__o21bai_2
  CLASS CORE ;
  SOURCE USER ;
  ORIGIN  0.000000  0.000000 ;
  SIZE  4.140000 BY  2.720000 ;
  SYMMETRY X Y R90 ;
  SITE unithd ;
  PIN A1
    ANTENNAGATEAREA  0.495000 ;
    DIRECTION INPUT ;
    USE SIGNAL ;
    PORT
      LAYER li1 ;
        RECT 3.260000 1.075000 4.055000 1.275000 ;
    END
  END A1
  PIN A2
    ANTENNAGATEAREA  0.495000 ;
    DIRECTION INPUT ;
    USE SIGNAL ;
    PORT
      LAYER li1 ;
        RECT 1.950000 1.075000 3.090000 1.275000 ;
    END
  END A2
  PIN B1_N
    ANTENNAGATEAREA  0.126000 ;
    DIRECTION INPUT ;
    USE SIGNAL ;
    PORT
      LAYER li1 ;
        RECT 0.085000 0.995000 0.525000 1.325000 ;
    END
  END B1_N
  PIN Y
    ANTENNADIFFAREA  0.715500 ;
    DIRECTION OUTPUT ;
    USE SIGNAL ;
    PORT
      LAYER li1 ;
        RECT 1.085000 1.445000 2.650000 1.615000 ;
        RECT 1.085000 1.615000 1.255000 2.465000 ;
        RECT 1.525000 0.645000 1.855000 0.905000 ;
        RECT 1.525000 0.905000 1.780000 1.445000 ;
        RECT 2.405000 1.615000 2.650000 2.125000 ;
    END
  END Y
  PIN VGND
    DIRECTION INOUT ;
    SHAPE ABUTMENT ;
    USE GROUND ;
    PORT
      LAYER li1 ;
        RECT 0.000000 -0.085000 4.140000 0.085000 ;
        RECT 0.180000  0.085000 0.350000 0.825000 ;
        RECT 2.445000  0.085000 2.615000 0.555000 ;
        RECT 3.285000  0.085000 3.455000 0.555000 ;
    END
    PORT
      LAYER met1 ;
        RECT 0.000000 -0.240000 4.140000 0.240000 ;
    END
  END VGND
  PIN VPWR
    DIRECTION INOUT ;
    SHAPE ABUTMENT ;
    USE POWER ;
    PORT
      LAYER li1 ;
        RECT 0.000000 2.635000 4.140000 2.805000 ;
        RECT 0.585000 1.875000 0.915000 2.635000 ;
        RECT 1.470000 1.795000 1.720000 2.635000 ;
        RECT 3.205000 1.835000 3.535000 2.635000 ;
    END
    PORT
      LAYER met1 ;
        RECT 0.000000 2.480000 4.140000 2.960000 ;
    END
  END VPWR
  OBS
    LAYER li1 ;
      RECT 0.180000 1.495000 0.865000 1.665000 ;
      RECT 0.180000 1.665000 0.350000 1.915000 ;
      RECT 0.600000 0.445000 0.865000 0.825000 ;
      RECT 0.695000 0.825000 0.865000 1.075000 ;
      RECT 0.695000 1.075000 1.335000 1.245000 ;
      RECT 0.695000 1.245000 0.865000 1.495000 ;
      RECT 1.075000 0.255000 2.275000 0.475000 ;
      RECT 1.075000 0.475000 1.355000 0.905000 ;
      RECT 1.955000 1.795000 2.235000 2.295000 ;
      RECT 1.955000 2.295000 3.035000 2.465000 ;
      RECT 2.025000 0.475000 2.275000 0.725000 ;
      RECT 2.025000 0.725000 3.980000 0.905000 ;
      RECT 2.785000 0.255000 3.115000 0.725000 ;
      RECT 2.865000 1.455000 3.980000 1.665000 ;
      RECT 2.865000 1.665000 3.035000 2.295000 ;
      RECT 3.625000 0.265000 3.980000 0.725000 ;
      RECT 3.705000 1.665000 3.980000 2.465000 ;
  END
END sky130_fd_sc_hd__o21bai_2
MACRO sky130_fd_sc_hd__or2_2
  CLASS CORE ;
  SOURCE USER ;
  ORIGIN  0.000000  0.000000 ;
  SIZE  2.300000 BY  2.720000 ;
  SYMMETRY X Y R90 ;
  SITE unithd ;
  PIN A
    ANTENNAGATEAREA  0.126000 ;
    DIRECTION INPUT ;
    USE SIGNAL ;
    PORT
      LAYER li1 ;
        RECT 0.865000 0.765000 1.275000 1.325000 ;
    END
  END A
  PIN B
    ANTENNAGATEAREA  0.126000 ;
    DIRECTION INPUT ;
    USE SIGNAL ;
    PORT
      LAYER li1 ;
        RECT 0.150000 0.765000 0.345000 1.325000 ;
    END
  END B
  PIN X
    ANTENNADIFFAREA  0.445500 ;
    DIRECTION OUTPUT ;
    USE SIGNAL ;
    PORT
      LAYER li1 ;
        RECT 1.440000 1.835000 2.215000 2.005000 ;
        RECT 1.440000 2.005000 1.770000 2.465000 ;
        RECT 1.520000 0.385000 1.690000 0.655000 ;
        RECT 1.520000 0.655000 2.215000 0.825000 ;
        RECT 1.785000 0.825000 2.215000 1.835000 ;
    END
  END X
  PIN VGND
    DIRECTION INOUT ;
    SHAPE ABUTMENT ;
    USE GROUND ;
    PORT
      LAYER li1 ;
        RECT 0.000000 -0.085000 2.300000 0.085000 ;
        RECT 0.105000  0.085000 0.345000 0.595000 ;
        RECT 1.035000  0.085000 1.350000 0.595000 ;
        RECT 1.860000  0.085000 2.190000 0.485000 ;
    END
    PORT
      LAYER met1 ;
        RECT 0.000000 -0.240000 2.300000 0.240000 ;
    END
  END VGND
  PIN VPWR
    DIRECTION INOUT ;
    SHAPE ABUTMENT ;
    USE POWER ;
    PORT
      LAYER li1 ;
        RECT 0.000000 2.635000 2.300000 2.805000 ;
        RECT 1.100000 1.835000 1.270000 2.635000 ;
        RECT 1.940000 2.175000 2.110000 2.635000 ;
    END
    PORT
      LAYER met1 ;
        RECT 0.000000 2.480000 2.300000 2.960000 ;
    END
  END VPWR
  OBS
    LAYER li1 ;
      RECT 0.155000 1.495000 1.615000 1.665000 ;
      RECT 0.155000 1.665000 0.515000 1.840000 ;
      RECT 0.515000 0.255000 0.805000 0.595000 ;
      RECT 0.515000 0.595000 0.695000 1.495000 ;
      RECT 1.445000 0.995000 1.615000 1.495000 ;
  END
END sky130_fd_sc_hd__or2_2
MACRO sky130_fd_sc_hd__tapvpwrvgnd_1
  CLASS CORE WELLTAP ;
  SOURCE USER ;
  ORIGIN  0.000000  0.000000 ;
  SIZE  0.460000 BY  2.720000 ;
  SYMMETRY X Y R90 ;
  SITE unithd ;
  PIN VGND
    DIRECTION INOUT ;
    SHAPE ABUTMENT ;
    USE GROUND ;
    PORT
      LAYER li1 ;
        RECT 0.000000 -0.085000 0.460000 0.085000 ;
        RECT 0.085000  0.085000 0.375000 0.810000 ;
    END
    PORT
      LAYER met1 ;
        RECT 0.000000 -0.240000 0.460000 0.240000 ;
    END
  END VGND
  PIN VPWR
    DIRECTION INOUT ;
    SHAPE ABUTMENT ;
    USE POWER ;
    PORT
      LAYER li1 ;
        RECT 0.000000 2.635000 0.460000 2.805000 ;
        RECT 0.085000 1.470000 0.375000 2.635000 ;
    END
    PORT
      LAYER met1 ;
        RECT 0.000000 2.480000 0.460000 2.960000 ;
    END
  END VPWR
  OBS
  END
END sky130_fd_sc_hd__tapvpwrvgnd_1
MACRO sky130_fd_sc_hd__xnor2_2
  CLASS CORE ;
  SOURCE USER ;
  ORIGIN  0.000000  0.000000 ;
  SIZE  5.980000 BY  2.720000 ;
  SYMMETRY X Y R90 ;
  SITE unithd ;
  PIN A
    ANTENNAGATEAREA  0.990000 ;
    DIRECTION INPUT ;
    USE SIGNAL ;
    PORT
      LAYER li1 ;
        RECT 1.255000 1.075000 2.705000 1.275000 ;
    END
  END A
  PIN B
    ANTENNAGATEAREA  0.990000 ;
    DIRECTION INPUT ;
    USE SIGNAL ;
    PORT
      LAYER li1 ;
        RECT 0.485000 1.075000 0.960000 1.285000 ;
        RECT 0.790000 1.285000 0.960000 1.445000 ;
        RECT 0.790000 1.445000 3.100000 1.615000 ;
        RECT 2.930000 1.075000 3.955000 1.285000 ;
        RECT 2.930000 1.285000 3.100000 1.445000 ;
    END
  END B
  PIN Y
    ANTENNADIFFAREA  0.913000 ;
    DIRECTION OUTPUT ;
    USE SIGNAL ;
    PORT
      LAYER li1 ;
        RECT 3.725000 1.795000 5.295000 1.965000 ;
        RECT 3.725000 1.965000 3.935000 2.125000 ;
        RECT 4.585000 0.305000 5.895000 0.475000 ;
        RECT 5.045000 1.415000 5.895000 1.625000 ;
        RECT 5.045000 1.625000 5.295000 1.795000 ;
        RECT 5.045000 1.965000 5.295000 2.125000 ;
        RECT 5.505000 0.475000 5.895000 1.415000 ;
    END
  END Y
  PIN VGND
    DIRECTION INOUT ;
    SHAPE ABUTMENT ;
    USE GROUND ;
    PORT
      LAYER li1 ;
        RECT 0.000000 -0.085000 5.980000 0.085000 ;
        RECT 1.450000  0.085000 1.620000 0.555000 ;
        RECT 2.430000  0.085000 2.600000 0.905000 ;
        RECT 3.270000  0.085000 3.440000 0.555000 ;
        RECT 4.145000  0.085000 4.315000 0.555000 ;
    END
    PORT
      LAYER met1 ;
        RECT 0.000000 -0.240000 5.980000 0.240000 ;
    END
  END VGND
  PIN VPWR
    DIRECTION INOUT ;
    SHAPE ABUTMENT ;
    USE POWER ;
    PORT
      LAYER li1 ;
        RECT 0.000000 2.635000 5.980000 2.805000 ;
        RECT 0.570000 2.135000 0.820000 2.635000 ;
        RECT 1.410000 2.135000 1.660000 2.635000 ;
        RECT 2.810000 2.135000 3.060000 2.635000 ;
        RECT 4.625000 2.135000 4.875000 2.635000 ;
        RECT 5.465000 1.795000 5.895000 2.635000 ;
    END
    PORT
      LAYER met1 ;
        RECT 0.000000 2.480000 5.980000 2.960000 ;
    END
  END VPWR
  OBS
    LAYER li1 ;
      RECT 0.085000 0.645000 0.860000 0.895000 ;
      RECT 0.085000 0.895000 0.315000 1.785000 ;
      RECT 0.085000 1.785000 3.480000 1.955000 ;
      RECT 0.085000 1.955000 2.080000 1.965000 ;
      RECT 0.085000 1.965000 0.400000 2.465000 ;
      RECT 0.105000 0.255000 1.280000 0.475000 ;
      RECT 0.990000 1.965000 1.240000 2.465000 ;
      RECT 1.030000 0.475000 1.280000 0.725000 ;
      RECT 1.030000 0.725000 2.120000 0.905000 ;
      RECT 1.790000 0.255000 2.120000 0.725000 ;
      RECT 1.830000 1.965000 2.080000 2.465000 ;
      RECT 2.390000 2.125000 2.640000 2.465000 ;
      RECT 2.770000 0.255000 3.100000 0.725000 ;
      RECT 2.770000 0.725000 5.335000 0.905000 ;
      RECT 3.230000 2.125000 3.555000 2.295000 ;
      RECT 3.230000 2.295000 4.355000 2.465000 ;
      RECT 3.310000 1.455000 4.805000 1.625000 ;
      RECT 3.310000 1.625000 3.480000 1.785000 ;
      RECT 3.610000 0.255000 3.975000 0.725000 ;
      RECT 4.105000 2.135000 4.355000 2.295000 ;
      RECT 4.635000 1.075000 5.295000 1.245000 ;
      RECT 4.635000 1.245000 4.805000 1.455000 ;
      RECT 5.005000 0.645000 5.335000 0.725000 ;
    LAYER mcon ;
      RECT 2.465000 2.125000 2.635000 2.295000 ;
      RECT 3.385000 2.125000 3.555000 2.295000 ;
    LAYER met1 ;
      RECT 2.405000 2.095000 2.695000 2.140000 ;
      RECT 2.405000 2.140000 3.615000 2.280000 ;
      RECT 2.405000 2.280000 2.695000 2.325000 ;
      RECT 3.325000 2.095000 3.615000 2.140000 ;
      RECT 3.325000 2.280000 3.615000 2.325000 ;
  END
END sky130_fd_sc_hd__xnor2_2
MACRO sky130_fd_sc_hd__xor2_2
  CLASS CORE ;
  SOURCE USER ;
  ORIGIN  0.000000  0.000000 ;
  SIZE  5.980000 BY  2.720000 ;
  SYMMETRY X Y R90 ;
  SITE unithd ;
  PIN A
    ANTENNAGATEAREA  0.990000 ;
    DIRECTION INPUT ;
    USE SIGNAL ;
    PORT
      LAYER li1 ;
        RECT 0.545000 1.075000 0.875000 1.275000 ;
        RECT 0.705000 1.275000 0.875000 1.445000 ;
        RECT 0.705000 1.445000 1.880000 1.615000 ;
        RECT 1.710000 1.075000 3.230000 1.275000 ;
        RECT 1.710000 1.275000 1.880000 1.445000 ;
    END
  END A
  PIN B
    ANTENNAGATEAREA  0.990000 ;
    DIRECTION INPUT ;
    USE SIGNAL ;
    PORT
      LAYER li1 ;
        RECT 1.045000 1.075000 1.540000 1.275000 ;
    END
    PORT
      LAYER li1 ;
        RECT 3.420000 1.075000 4.090000 1.275000 ;
    END
    PORT
      LAYER met1 ;
        RECT 1.005000 1.075000 1.295000 1.120000 ;
        RECT 1.005000 1.120000 4.055000 1.260000 ;
        RECT 1.005000 1.260000 1.295000 1.305000 ;
        RECT 3.765000 1.075000 4.055000 1.120000 ;
        RECT 3.765000 1.260000 4.055000 1.305000 ;
    END
  END B
  PIN X
    ANTENNADIFFAREA  0.656750 ;
    DIRECTION OUTPUT ;
    USE SIGNAL ;
    PORT
      LAYER li1 ;
        RECT 3.625000 0.645000 3.955000 0.725000 ;
        RECT 3.625000 0.725000 5.895000 0.905000 ;
        RECT 4.985000 0.645000 5.315000 0.725000 ;
        RECT 5.025000 1.415000 5.895000 1.625000 ;
        RECT 5.025000 1.625000 5.275000 2.125000 ;
        RECT 5.485000 0.905000 5.895000 1.415000 ;
    END
  END X
  PIN VGND
    DIRECTION INOUT ;
    SHAPE ABUTMENT ;
    USE GROUND ;
    PORT
      LAYER li1 ;
        RECT 0.000000 -0.085000 5.980000 0.085000 ;
        RECT 0.190000  0.085000 0.360000 0.555000 ;
        RECT 1.030000  0.085000 1.200000 0.555000 ;
        RECT 1.870000  0.085000 2.040000 0.555000 ;
        RECT 2.810000  0.085000 2.980000 0.555000 ;
        RECT 4.645000  0.085000 4.815000 0.555000 ;
        RECT 5.485000  0.085000 5.655000 0.555000 ;
    END
    PORT
      LAYER met1 ;
        RECT 0.000000 -0.240000 5.980000 0.240000 ;
    END
  END VGND
  PIN VPWR
    DIRECTION INOUT ;
    SHAPE ABUTMENT ;
    USE POWER ;
    PORT
      LAYER li1 ;
        RECT 0.000000 2.635000 5.980000 2.805000 ;
        RECT 0.570000 2.135000 0.820000 2.635000 ;
        RECT 2.770000 2.135000 3.020000 2.635000 ;
        RECT 3.610000 2.135000 3.915000 2.635000 ;
    END
    PORT
      LAYER met1 ;
        RECT 0.000000 2.480000 5.980000 2.960000 ;
    END
  END VPWR
  OBS
    LAYER li1 ;
      RECT 0.120000 0.725000 1.700000 0.905000 ;
      RECT 0.120000 0.905000 0.290000 1.785000 ;
      RECT 0.120000 1.785000 2.220000 1.955000 ;
      RECT 0.120000 2.135000 0.400000 2.465000 ;
      RECT 0.145000 2.125000 0.315000 2.135000 ;
      RECT 0.530000 0.255000 0.860000 0.725000 ;
      RECT 0.990000 2.135000 1.240000 2.295000 ;
      RECT 0.990000 2.295000 2.080000 2.465000 ;
      RECT 1.065000 2.125000 1.235000 2.135000 ;
      RECT 1.370000 0.255000 1.700000 0.725000 ;
      RECT 1.410000 1.955000 1.660000 2.125000 ;
      RECT 1.830000 2.135000 2.080000 2.295000 ;
      RECT 2.050000 1.445000 4.785000 1.615000 ;
      RECT 2.050000 1.615000 2.220000 1.785000 ;
      RECT 2.285000 2.125000 2.600000 2.465000 ;
      RECT 2.310000 0.255000 2.640000 0.725000 ;
      RECT 2.310000 0.725000 3.400000 0.905000 ;
      RECT 2.390000 1.785000 4.855000 1.955000 ;
      RECT 2.390000 1.955000 2.600000 2.125000 ;
      RECT 3.150000 0.255000 4.380000 0.475000 ;
      RECT 3.150000 0.475000 3.400000 0.725000 ;
      RECT 3.190000 1.955000 3.440000 2.465000 ;
      RECT 4.085000 1.955000 4.855000 2.295000 ;
      RECT 4.085000 2.295000 5.695000 2.465000 ;
      RECT 4.615000 1.075000 5.275000 1.245000 ;
      RECT 4.615000 1.245000 4.785000 1.445000 ;
      RECT 5.445000 1.795000 5.695000 2.295000 ;
    LAYER mcon ;
      RECT 0.145000 2.125000 0.315000 2.295000 ;
      RECT 1.065000 2.125000 1.235000 2.295000 ;
    LAYER met1 ;
      RECT 0.085000 2.095000 0.375000 2.140000 ;
      RECT 0.085000 2.140000 1.295000 2.280000 ;
      RECT 0.085000 2.280000 0.375000 2.325000 ;
      RECT 1.005000 2.095000 1.295000 2.140000 ;
      RECT 1.005000 2.280000 1.295000 2.325000 ;
  END
END sky130_fd_sc_hd__xor2_2
END LIBRARY
